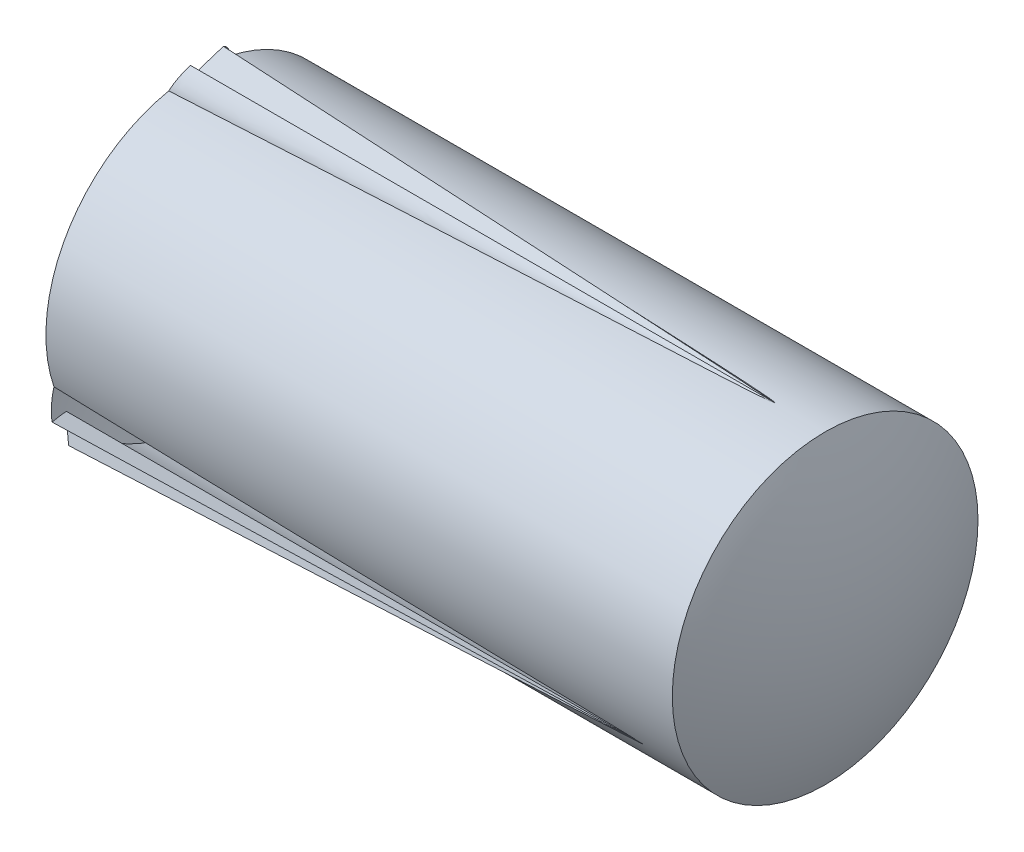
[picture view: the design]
ISO-10303-21;
HEADER;
FILE_DESCRIPTION(('STEP AP214'),'2;1');
FILE_NAME('part.step','',(''),(''),'','','');
FILE_SCHEMA(('AUTOMOTIVE_DESIGN { 1 0 10303 214 1 1 1 1 }'));
ENDSEC;
DATA;
#1=APPLICATION_CONTEXT('core data for automotive mechanical design processes');
#2=APPLICATION_PROTOCOL_DEFINITION('international standard','automotive_design',2000,#1);
#3=PRODUCT_CONTEXT('',#1,'mechanical');
#4=PRODUCT('Part','Part','',(#3));
#5=PRODUCT_RELATED_PRODUCT_CATEGORY('part','',(#4));
#6=PRODUCT_DEFINITION_FORMATION('','',#4);
#7=PRODUCT_DEFINITION_CONTEXT('part definition',#1,'design');
#8=PRODUCT_DEFINITION('design','',#6,#7);
#9=PRODUCT_DEFINITION_SHAPE('','',#8);
#10=(LENGTH_UNIT() NAMED_UNIT(*) SI_UNIT(.MILLI.,.METRE.));
#11=(NAMED_UNIT(*) PLANE_ANGLE_UNIT() SI_UNIT($,.RADIAN.));
#12=(NAMED_UNIT(*) SI_UNIT($,.STERADIAN.) SOLID_ANGLE_UNIT());
#13=UNCERTAINTY_MEASURE_WITH_UNIT(LENGTH_MEASURE(1.E-05),#10,'distance_accuracy_value','');
#14=(GEOMETRIC_REPRESENTATION_CONTEXT(3) GLOBAL_UNCERTAINTY_ASSIGNED_CONTEXT((#13)) GLOBAL_UNIT_ASSIGNED_CONTEXT((#10,
#11,#12)) REPRESENTATION_CONTEXT('',''));
#15=CARTESIAN_POINT('',(0.,0.,0.));
#16=DIRECTION('',(0.,0.,1.));
#17=DIRECTION('',(1.,0.,0.));
#18=AXIS2_PLACEMENT_3D('',#15,#16,#17);
#19=CARTESIAN_POINT('',(-1.5875,-0.291549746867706,0.495451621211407));
#20=CARTESIAN_POINT('',(1.3335,-0.372808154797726,0.644533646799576));
#21=CARTESIAN_POINT('',(-1.5875,-0.268799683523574,0.507669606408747));
#22=CARTESIAN_POINT('',(1.3335,-0.370586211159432,0.645702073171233));
#23=CARTESIAN_POINT('',(-1.5875,-0.24170191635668,0.529257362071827));
#24=CARTESIAN_POINT('',(1.3335,-0.36783750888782,0.648565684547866));
#25=CARTESIAN_POINT('',(-1.5875,-0.206920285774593,0.60421552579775));
#26=CARTESIAN_POINT('',(1.3335,-0.3646195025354,0.655930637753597));
#27=CARTESIAN_POINT('',(-1.5875,-0.203921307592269,0.659759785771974));
#28=CARTESIAN_POINT('',(1.3335,-0.364150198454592,0.660431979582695));
#29=CARTESIAN_POINT('',(-1.5875,-0.252793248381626,0.750760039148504));
#30=CARTESIAN_POINT('',(1.3335,-0.36882390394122,0.66931975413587));
#31=CARTESIAN_POINT('',(-1.5875,-0.300754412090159,0.778936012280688));
#32=CARTESIAN_POINT('',(1.3335,-0.372798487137,0.671484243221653));
#33=CARTESIAN_POINT('',(-1.5875,-0.38245310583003,0.791338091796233));
#34=CARTESIAN_POINT('',(1.3335,-0.380690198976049,0.673007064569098));
#35=CARTESIAN_POINT('',(-1.5875,-0.415415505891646,0.780670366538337));
#36=CARTESIAN_POINT('',(1.3335,-0.384607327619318,0.672365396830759));
#37=CARTESIAN_POINT('',(-1.5875,-0.460915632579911,0.756234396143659));
#38=CARTESIAN_POINT('',(1.3335,-0.389051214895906,0.670028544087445));
#39=CARTESIAN_POINT('',(-1.5875,-0.488013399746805,0.734646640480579));
#40=CARTESIAN_POINT('',(1.3335,-0.391799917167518,0.667164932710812));
#41=CARTESIAN_POINT('',(-1.5875,-0.522795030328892,0.659688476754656));
#42=CARTESIAN_POINT('',(1.3335,-0.395017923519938,0.659799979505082));
#43=CARTESIAN_POINT('',(-1.5875,-0.525794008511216,0.604144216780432));
#44=CARTESIAN_POINT('',(1.3335,-0.395487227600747,0.655298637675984));
#45=CARTESIAN_POINT('',(-1.5875,-0.476922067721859,0.513143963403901));
#46=CARTESIAN_POINT('',(1.3335,-0.390813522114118,0.646410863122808));
#47=CARTESIAN_POINT('',(-1.5875,-0.428960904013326,0.484967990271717));
#48=CARTESIAN_POINT('',(1.3335,-0.386838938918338,0.644246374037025));
#49=CARTESIAN_POINT('',(-1.5875,-0.347262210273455,0.472565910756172));
#50=CARTESIAN_POINT('',(1.3335,-0.378947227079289,0.64272355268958));
#51=CARTESIAN_POINT('',(-1.5875,-0.314299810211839,0.483233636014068));
#52=CARTESIAN_POINT('',(1.3335,-0.37503009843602,0.643365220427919));
#53=CARTESIAN_POINT('',(-1.5875,-0.291549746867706,0.495451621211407));
#54=CARTESIAN_POINT('',(1.3335,-0.372808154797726,0.644533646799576));
#55=B_SPLINE_SURFACE_WITH_KNOTS('',3,1,((#19,#20),(#21,#22),(#23,#24),(#25,#26),(#27,#28),(#29,
#30),(#31,#32),(#33,#34),(#35,#36),(#37,#38),(#39,#40),(#41,#42),(#43,#44),(#45,#46),(#47,#48),
(#49,#50),(#51,#52),(#53,#54)),.UNSPECIFIED.,.T.,.F.,.F.,(4,2,2,2,2,2,2,2,4),(2,2),(0.,0.125,
0.25,0.375,0.5,0.625,0.75,0.875,1.),(0.,1.),.UNSPECIFIED.);
#56=CARTESIAN_POINT('',(1.3332323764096,-0.387350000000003,0.670909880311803));
#57=CARTESIAN_POINT('',(1.32702789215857,-0.387657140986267,0.670992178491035));
#58=CARTESIAN_POINT('',(1.32082308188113,-0.387957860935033,0.671072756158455));
#59=CARTESIAN_POINT('',(1.28979763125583,-0.389434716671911,0.671468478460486));
#60=CARTESIAN_POINT('',(1.26497293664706,-0.390530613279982,0.671762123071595));
#61=CARTESIAN_POINT('',(1.14084574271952,-0.395925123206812,0.673207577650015));
#62=CARTESIAN_POINT('',(1.04153188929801,-0.399968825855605,0.674291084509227));
#63=CARTESIAN_POINT('',(0.743585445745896,-0.411975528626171,0.677508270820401));
#64=CARTESIAN_POINT('',(0.544947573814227,-0.419814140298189,0.679608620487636));
#65=CARTESIAN_POINT('',(0.0240320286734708,-0.440289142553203,0.685094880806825));
#66=CARTESIAN_POINT('',(-0.298247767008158,-0.452875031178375,0.688467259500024));
#67=CARTESIAN_POINT('',(-0.942809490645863,-0.477996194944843,0.695198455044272));
#68=CARTESIAN_POINT('',(-1.26509141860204,-0.490531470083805,0.698557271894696));
#69=CARTESIAN_POINT('',(-1.58737204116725,-0.50309757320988,0.701924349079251));
#70=B_SPLINE_CURVE_WITH_KNOTS('',3,(#56,#57,#58,#59,#60,#61,#62,#63,#64,#65,#66,#67,#68,#69),
.UNSPECIFIED.,.F.,.F.,(4,2,2,2,2,2,4),(0.,0.0186378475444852,0.0931893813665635,
0.391395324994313,0.987806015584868,1.95543526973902,2.9230645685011),.UNSPECIFIED.);
#71=CARTESIAN_POINT('',(1.33323237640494,-0.387350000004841,0.67090988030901));
#72=VERTEX_POINT('',#71);
#73=CARTESIAN_POINT('',(-1.54566934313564,-0.50147437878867,0.701489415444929));
#74=VERTEX_POINT('',#73);
#75=EDGE_CURVE('E84',#72,#74,#70,.T.);
#76=CARTESIAN_POINT('',(-1.54500744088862,-0.500125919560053,0.704044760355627));
#77=CARTESIAN_POINT('',(-1.54679609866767,-0.503995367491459,0.696996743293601));
#78=CARTESIAN_POINT('',(-1.54884127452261,-0.507167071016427,0.689682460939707));
#79=CARTESIAN_POINT('',(-1.55330634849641,-0.512259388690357,0.674759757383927));
#80=CARTESIAN_POINT('',(-1.55572508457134,-0.514183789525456,0.667152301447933));
#81=CARTESIAN_POINT('',(-1.56094778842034,-0.517021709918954,0.651425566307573));
#82=CARTESIAN_POINT('',(-1.56376545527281,-0.51787552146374,0.643300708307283));
#83=CARTESIAN_POINT('',(-1.56960974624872,-0.518430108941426,0.627076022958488));
#84=CARTESIAN_POINT('',(-1.57263654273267,-0.518129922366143,0.618976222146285));
#85=CARTESIAN_POINT('',(-1.57765132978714,-0.516704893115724,0.606038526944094));
#86=CARTESIAN_POINT('',(-1.57959276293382,-0.51594027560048,0.601140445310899));
#87=CARTESIAN_POINT('',(-1.58351689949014,-0.513963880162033,0.591468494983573));
#88=CARTESIAN_POINT('',(-1.58549947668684,-0.512753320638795,0.58669432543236));
#89=CARTESIAN_POINT('',(-1.5875,-0.511315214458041,0.581993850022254));
#90=B_SPLINE_CURVE_WITH_KNOTS('',3,(#76,#77,#78,#79,#80,#81,#82,#83,#84,#85,#86,#87,#88,#89),
.UNSPECIFIED.,.F.,.F.,(4,2,2,2,2,2,4),(0.,0.0246089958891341,0.0491429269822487,
0.0749917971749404,0.100862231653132,0.116815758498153,0.132726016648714),.UNSPECIFIED.);
#91=CARTESIAN_POINT('',(-1.5875,-0.511417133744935,0.581904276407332));
#92=VERTEX_POINT('',#91);
#93=EDGE_CURVE('E163',#74,#92,#90,.T.);
#94=CARTESIAN_POINT('',(-1.5875,-0.511315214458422,0.581993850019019));
#95=CARTESIAN_POINT('',(-1.5510388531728,-0.509953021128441,0.583190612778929));
#96=CARTESIAN_POINT('',(-1.51457762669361,-0.508587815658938,0.584381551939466));
#97=CARTESIAN_POINT('',(-1.33227107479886,-0.501746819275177,0.590307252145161));
#98=CARTESIAN_POINT('',(-1.18642459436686,-0.496226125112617,0.594955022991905));
#99=CARTESIAN_POINT('',(-0.894729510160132,-0.485091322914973,0.604068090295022));
#100=CARTESIAN_POINT('',(-0.748880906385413,-0.479477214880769,0.608533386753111));
#101=CARTESIAN_POINT('',(-0.457182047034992,-0.468154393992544,0.617286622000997));
#102=CARTESIAN_POINT('',(-0.311331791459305,-0.462445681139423,0.62157456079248));
#103=CARTESIAN_POINT('',(-0.0925559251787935,-0.453803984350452,0.627881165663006));
#104=CARTESIAN_POINT('',(-0.0196305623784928,-0.4509103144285,0.629962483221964));
#105=CARTESIAN_POINT('',(0.0897573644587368,-0.446546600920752,0.633055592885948));
#106=CARTESIAN_POINT('',(0.126219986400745,-0.445088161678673,0.634081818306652));
#107=CARTESIAN_POINT('',(0.308533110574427,-0.43777766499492,0.639188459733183));
#108=CARTESIAN_POINT('',(0.454383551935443,-0.431870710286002,0.643195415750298));
#109=CARTESIAN_POINT('',(0.673186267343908,-0.422813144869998,0.649154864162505));
#110=CARTESIAN_POINT('',(0.746141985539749,-0.41976036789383,0.651133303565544));
#111=CARTESIAN_POINT('',(0.891980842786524,-0.413540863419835,0.655101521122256));
#112=CARTESIAN_POINT('',(0.964863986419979,-0.41037424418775,0.65709128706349));
#113=CARTESIAN_POINT('',(1.07413626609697,-0.405328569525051,0.660206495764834));
#114=CARTESIAN_POINT('',(1.11053428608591,-0.403598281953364,0.661266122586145));
#115=CARTESIAN_POINT('',(1.1834214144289,-0.399887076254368,0.663517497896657));
#116=CARTESIAN_POINT('',(1.21991047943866,-0.397905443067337,0.664709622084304));
#117=CARTESIAN_POINT('',(1.27307232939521,-0.39436826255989,0.666810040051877));
#118=CARTESIAN_POINT('',(1.2897735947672,-0.393163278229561,0.667522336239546));
#119=CARTESIAN_POINT('',(1.31222269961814,-0.390998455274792,0.668790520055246));
#120=CARTESIAN_POINT('',(1.31800869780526,-0.390391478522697,0.669145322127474));
#121=CARTESIAN_POINT('',(1.32577045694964,-0.389280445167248,0.669791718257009));
#122=CARTESIAN_POINT('',(1.32777879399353,-0.388965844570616,0.669974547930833));
#123=CARTESIAN_POINT('',(1.33049611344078,-0.388382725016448,0.670312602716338));
#124=CARTESIAN_POINT('',(1.33122779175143,-0.38820969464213,0.670412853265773));
#125=CARTESIAN_POINT('',(1.33219296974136,-0.387896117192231,0.670594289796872));
#126=CARTESIAN_POINT('',(1.33244633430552,-0.387805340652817,0.670646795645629));
#127=CARTESIAN_POINT('',(1.33278210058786,-0.387650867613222,0.670736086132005));
#128=CARTESIAN_POINT('',(1.33287397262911,-0.387604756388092,0.670762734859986));
#129=CARTESIAN_POINT('',(1.33303654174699,-0.387508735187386,0.670818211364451));
#130=CARTESIAN_POINT('',(1.33310843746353,-0.387460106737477,0.670846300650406));
#131=CARTESIAN_POINT('',(1.33324349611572,-0.387346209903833,0.670912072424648));
#132=CARTESIAN_POINT('',(1.33330652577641,-0.387280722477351,0.670949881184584));
#133=CARTESIAN_POINT('',(1.33335671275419,-0.387130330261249,0.671036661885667));
#134=CARTESIAN_POINT('',(1.33334808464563,-0.387046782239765,0.671084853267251));
#135=CARTESIAN_POINT('',(1.33324399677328,-0.386814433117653,0.671218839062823));
#136=CARTESIAN_POINT('',(1.33305205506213,-0.386717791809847,0.671274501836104));
#137=CARTESIAN_POINT('',(1.33262977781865,-0.386527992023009,0.671383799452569));
#138=CARTESIAN_POINT('',(1.33240356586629,-0.386443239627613,0.671432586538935));
#139=CARTESIAN_POINT('',(1.33193531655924,-0.386291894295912,0.671519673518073));
#140=CARTESIAN_POINT('',(1.33169349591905,-0.386225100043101,0.671558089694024));
#141=CARTESIAN_POINT('',(1.33089374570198,-0.38601912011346,0.671676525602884));
#142=CARTESIAN_POINT('',(1.33033361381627,-0.385898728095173,0.67174569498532));
#143=CARTESIAN_POINT('',(1.32921036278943,-0.385677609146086,0.671872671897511));
#144=CARTESIAN_POINT('',(1.32864729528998,-0.385576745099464,0.671930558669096));
#145=CARTESIAN_POINT('',(1.32717273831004,-0.385328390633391,0.672073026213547));
#146=CARTESIAN_POINT('',(1.32625954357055,-0.385190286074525,0.67215218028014));
#147=CARTESIAN_POINT('',(1.32142647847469,-0.384497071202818,0.67254927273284));
#148=CARTESIAN_POINT('',(1.31748371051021,-0.384062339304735,0.67279749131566));
#149=CARTESIAN_POINT('',(1.30924317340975,-0.383224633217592,0.67327496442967));
#150=CARTESIAN_POINT('',(1.30494478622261,-0.382827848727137,0.673500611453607));
#151=CARTESIAN_POINT('',(1.28387217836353,-0.380984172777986,0.67454737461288));
#152=CARTESIAN_POINT('',(1.26706339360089,-0.379828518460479,0.675197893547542));
#153=CARTESIAN_POINT('',(1.23399421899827,-0.377699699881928,0.676390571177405));
#154=CARTESIAN_POINT('',(1.21773411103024,-0.376721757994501,0.676935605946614));
#155=CARTESIAN_POINT('',(1.16859487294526,-0.373902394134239,0.678499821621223));
#156=CARTESIAN_POINT('',(1.13570433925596,-0.372199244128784,0.679434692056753));
#157=CARTESIAN_POINT('',(1.0699157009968,-0.368919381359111,0.681220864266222));
#158=CARTESIAN_POINT('',(1.03701759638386,-0.367342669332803,0.682072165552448));
#159=CARTESIAN_POINT('',(0.937508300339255,-0.362662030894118,0.684579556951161));
#160=CARTESIAN_POINT('',(0.870890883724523,-0.359648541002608,0.686166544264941));
#161=CARTESIAN_POINT('',(0.737944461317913,-0.353691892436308,0.689255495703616));
#162=CARTESIAN_POINT('',(0.671615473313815,-0.350748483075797,0.690757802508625));
#163=CARTESIAN_POINT('',(0.539188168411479,-0.344890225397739,0.693701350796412));
#164=CARTESIAN_POINT('',(0.47308985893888,-0.341975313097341,0.69514278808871));
#165=CARTESIAN_POINT('',(0.274631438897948,-0.333218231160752,0.699405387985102));
#166=CARTESIAN_POINT('',(0.14227017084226,-0.327370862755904,0.702161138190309));
#167=CARTESIAN_POINT('',(-0.122593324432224,-0.315602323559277,0.707528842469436));
#168=CARTESIAN_POINT('',(-0.255095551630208,-0.309681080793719,0.710140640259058));
#169=CARTESIAN_POINT('',(-0.520028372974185,-0.297758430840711,0.715221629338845));
#170=CARTESIAN_POINT('',(-0.65245896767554,-0.291757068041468,0.717690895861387));
#171=CARTESIAN_POINT('',(-0.916206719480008,-0.279714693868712,0.722468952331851));
#172=CARTESIAN_POINT('',(-1.04752388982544,-0.273674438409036,0.724778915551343));
#173=CARTESIAN_POINT('',(-1.31506113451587,-0.261275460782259,0.729342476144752));
#174=CARTESIAN_POINT('',(-1.45128113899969,-0.254913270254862,0.731590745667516));
#175=CARTESIAN_POINT('',(-1.5875,-0.248500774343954,0.733762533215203));
#176=B_SPLINE_CURVE_WITH_KNOTS('',3,(#94,#95,#96,#97,#98,#99,#100,#101,#102,#103,#104,#105,#106,
#107,#108,#109,#110,#111,#112,#113,#114,#115,#116,#117,#118,#119,#120,#121,#122,#123,#124,#125,
#126,#127,#128,#129,#130,#131,#132,#133,#134,#135,#136,#137,#138,#139,#140,#141,#142,#143,#144,
#145,#146,#147,#148,#149,#150,#151,#152,#153,#154,#155,#156,#157,#158,#159,#160,#161,#162,#163,
#164,#165,#166,#167,#168,#169,#170,#171,#172,#173,#174,#175),.UNSPECIFIED.,.F.,.F.,(4,2,2,2,2,2,
2,2,2,2,2,2,2,2,2,2,2,2,2,2,2,2,2,2,2,2,2,2,2,2,2,2,2,2,2,2,2,2,2,2,4),(0.,0.109518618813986,
0.547593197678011,0.985667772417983,1.42374234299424,1.64277958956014,1.75229820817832,
2.19037278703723,2.40951203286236,2.62844811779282,2.73781196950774,2.84749424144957,
2.89776892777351,2.91524734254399,2.92136717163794,2.92363754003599,2.92445864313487,
2.92477568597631,2.92505134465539,2.92533078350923,2.92559390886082,2.92619169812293,
2.92695534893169,2.92771004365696,2.92944599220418,2.93116927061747,2.93395039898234,
2.94586710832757,2.95883561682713,3.00940854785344,3.05830591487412,3.15714640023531,
3.25598746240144,3.45609991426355,3.65533383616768,3.85386853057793,4.25142551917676,
4.64940594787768,5.04717435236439,5.44160317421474,5.8507641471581),.UNSPECIFIED.);
#177=EDGE_CURVE('E242',#92,#72,#176,.T.);
#178=ORIENTED_EDGE('',*,*,#75,.T.);
#179=ORIENTED_EDGE('',*,*,#93,.T.);
#180=ORIENTED_EDGE('',*,*,#177,.T.);
#181=EDGE_LOOP('',(#178,#179,#180));
#182=FACE_BOUND('',#181,.T.);
#183=ADVANCED_FACE('F73',(#182),#55,.T.);
#184=CARTESIAN_POINT('',(-1.58749999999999,-0.248339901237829,0.733812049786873));
#185=VERTEX_POINT('',#184);
#186=EDGE_CURVE('E156',#72,#185,#176,.T.);
#187=CARTESIAN_POINT('',(-1.58749999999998,-0.248500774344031,0.733762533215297));
#188=CARTESIAN_POINT('',(-1.58403028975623,-0.254337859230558,0.739990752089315));
#189=CARTESIAN_POINT('',(-1.58060899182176,-0.260678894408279,0.745758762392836));
#190=CARTESIAN_POINT('',(-1.57388632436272,-0.274300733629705,0.756346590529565));
#191=CARTESIAN_POINT('',(-1.57058676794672,-0.281591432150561,0.761154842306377));
#192=CARTESIAN_POINT('',(-1.56373468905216,-0.29805306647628,0.770286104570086));
#193=CARTESIAN_POINT('',(-1.56021844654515,-0.307342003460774,0.774428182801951));
#194=CARTESIAN_POINT('',(-1.55531311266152,-0.321819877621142,0.779277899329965));
#195=CARTESIAN_POINT('',(-1.55374297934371,-0.326723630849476,0.780665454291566));
#196=CARTESIAN_POINT('',(-1.55077705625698,-0.336706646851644,0.782878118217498));
#197=CARTESIAN_POINT('',(-1.54938117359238,-0.341785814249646,0.783703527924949));
#198=CARTESIAN_POINT('',(-1.54699295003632,-0.351115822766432,0.78473995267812));
#199=CARTESIAN_POINT('',(-1.54597327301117,-0.355350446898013,0.785035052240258));
#200=CARTESIAN_POINT('',(-1.5450074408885,-0.359596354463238,0.785172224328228));
#201=B_SPLINE_CURVE_WITH_KNOTS('',3,(#187,#188,#189,#190,#191,#192,#193,#194,#195,#196,#197,
#198,#199,#200),.UNSPECIFIED.,.F.,.F.,(4,2,2,2,2,2,4),(0.,0.027599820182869,0.0555144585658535,
0.0876157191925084,0.103586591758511,0.119548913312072,0.132626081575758),.UNSPECIFIED.);
#202=CARTESIAN_POINT('',(-1.54565892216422,-0.356763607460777,0.785059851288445));
#203=VERTEX_POINT('',#202);
#204=EDGE_CURVE('E155',#185,#203,#201,.T.);
#205=CARTESIAN_POINT('',(-1.58669387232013,-0.356335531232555,0.78665745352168));
#206=CARTESIAN_POINT('',(-1.55021728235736,-0.356716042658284,0.785237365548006));
#207=CARTESIAN_POINT('',(-1.51374069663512,-0.357096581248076,0.78381717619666));
#208=CARTESIAN_POINT('',(-1.33135779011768,-0.358999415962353,0.776715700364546));
#209=CARTESIAN_POINT('',(-1.18545153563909,-0.360522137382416,0.771032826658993));
#210=CARTESIAN_POINT('',(-0.747733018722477,-0.365091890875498,0.753978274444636));
#211=CARTESIAN_POINT('',(-0.45592100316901,-0.368140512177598,0.742600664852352));
#212=CARTESIAN_POINT('',(-0.0182048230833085,-0.372725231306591,0.725490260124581));
#213=CARTESIAN_POINT('',(0.127700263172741,-0.374255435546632,0.719779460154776));
#214=CARTESIAN_POINT('',(0.419509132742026,-0.377324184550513,0.708326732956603));
#215=CARTESIAN_POINT('',(0.565412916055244,-0.378862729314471,0.702584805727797));
#216=CARTESIAN_POINT('',(0.763145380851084,-0.380965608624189,0.694736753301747));
#217=CARTESIAN_POINT('',(0.814975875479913,-0.381518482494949,0.692673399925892));
#218=CARTESIAN_POINT('',(0.918635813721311,-0.382630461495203,0.688523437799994));
#219=CARTESIAN_POINT('',(0.97046525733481,-0.383189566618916,0.686436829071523));
#220=CARTESIAN_POINT('',(1.07412285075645,-0.384318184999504,0.682224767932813));
#221=CARTESIAN_POINT('',(1.12595100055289,-0.384887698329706,0.680099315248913));
#222=CARTESIAN_POINT('',(1.20368942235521,-0.385765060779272,0.676824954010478));
#223=CARTESIAN_POINT('',(1.2296016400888,-0.38606136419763,0.675719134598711));
#224=CARTESIAN_POINT('',(1.26846768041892,-0.386519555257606,0.674009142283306));
#225=CARTESIAN_POINT('',(1.2814226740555,-0.386674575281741,0.673430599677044));
#226=CARTESIAN_POINT('',(1.30733001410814,-0.386999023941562,0.672219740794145));
#227=CARTESIAN_POINT('',(1.32028236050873,-0.387168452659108,0.671587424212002));
#228=CARTESIAN_POINT('',(1.3332323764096,-0.387350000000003,0.670909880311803));
#229=B_SPLINE_CURVE_WITH_KNOTS('',3,(#205,#206,#207,#208,#209,#210,#211,#212,#213,#214,#215,
#216,#217,#218,#219,#220,#221,#222,#223,#224,#225,#226,#227,#228),.UNSPECIFIED.,.F.,.F.,(4,2,2,
2,2,2,2,2,2,2,2,4),(0.,0.109518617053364,0.547593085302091,1.42374202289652,1.86181649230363,
2.29989096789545,2.45551444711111,2.61113778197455,2.7667622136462,2.84457469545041,
2.88348110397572,2.92238773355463),.UNSPECIFIED.);
#230=EDGE_CURVE('E95',#203,#72,#229,.T.);
#231=ORIENTED_EDGE('',*,*,#186,.T.);
#232=ORIENTED_EDGE('',*,*,#204,.T.);
#233=ORIENTED_EDGE('',*,*,#230,.T.);
#234=EDGE_LOOP('',(#231,#232,#233));
#235=FACE_BOUND('',#234,.T.);
#236=ADVANCED_FACE('F159',(#235),#55,.T.);
#237=CARTESIAN_POINT('',(-1.5875,-0.283298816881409,-0.500215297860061));
#238=CARTESIAN_POINT('',(1.3335,-0.371778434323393,-0.645128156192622));
#239=CARTESIAN_POINT('',(-1.5875,-0.305254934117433,-0.486622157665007));
#240=CARTESIAN_POINT('',(1.3335,-0.373901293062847,-0.643788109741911));
#241=CARTESIAN_POINT('',(-1.5875,-0.337499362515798,-0.473948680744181));
#242=CARTESIAN_POINT('',(1.3335,-0.377755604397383,-0.642839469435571));
#243=CARTESIAN_POINT('',(-1.5875,-0.419805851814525,-0.481305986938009));
#244=CARTESIAN_POINT('',(1.3335,-0.38574284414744,-0.643735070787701));
#245=CARTESIAN_POINT('',(-1.5875,-0.469408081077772,-0.506480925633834));
#246=CARTESIAN_POINT('',(1.3335,-0.38987577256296,-0.64557931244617));
#247=CARTESIAN_POINT('',(-1.5875,-0.523780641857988,-0.594305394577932));
#248=CARTESIAN_POINT('',(1.3335,-0.395235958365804,-0.654070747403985));
#249=CARTESIAN_POINT('',(-1.5875,-0.524201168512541,-0.649928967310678));
#250=CARTESIAN_POINT('',(1.3335,-0.395123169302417,-0.658595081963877));
#251=CARTESIAN_POINT('',(-1.5875,-0.494092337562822,-0.726883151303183));
#252=CARTESIAN_POINT('',(1.3335,-0.392496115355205,-0.666190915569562));
#253=CARTESIAN_POINT('',(-1.5875,-0.468372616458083,-0.7500955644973));
#254=CARTESIAN_POINT('',(1.3335,-0.38998185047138,-0.669262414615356));
#255=CARTESIAN_POINT('',(-1.5875,-0.424460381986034,-0.777281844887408));
#256=CARTESIAN_POINT('',(1.3335,-0.385736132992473,-0.671942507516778));
#257=CARTESIAN_POINT('',(-1.5875,-0.392215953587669,-0.789955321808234));
#258=CARTESIAN_POINT('',(1.3335,-0.381881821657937,-0.672891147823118));
#259=CARTESIAN_POINT('',(-1.5875,-0.309909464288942,-0.782598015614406));
#260=CARTESIAN_POINT('',(1.3335,-0.37389458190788,-0.671995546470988));
#261=CARTESIAN_POINT('',(-1.5875,-0.260307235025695,-0.757423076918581));
#262=CARTESIAN_POINT('',(1.3335,-0.36976165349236,-0.670151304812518));
#263=CARTESIAN_POINT('',(-1.5875,-0.205934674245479,-0.669598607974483));
#264=CARTESIAN_POINT('',(1.3335,-0.364401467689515,-0.661659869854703));
#265=CARTESIAN_POINT('',(-1.5875,-0.205514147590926,-0.613975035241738));
#266=CARTESIAN_POINT('',(1.3335,-0.364514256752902,-0.657135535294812));
#267=CARTESIAN_POINT('',(-1.5875,-0.235622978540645,-0.537020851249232));
#268=CARTESIAN_POINT('',(1.3335,-0.367141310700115,-0.649539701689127));
#269=CARTESIAN_POINT('',(-1.5875,-0.261342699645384,-0.513808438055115));
#270=CARTESIAN_POINT('',(1.3335,-0.36965557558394,-0.646468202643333));
#271=CARTESIAN_POINT('',(-1.5875,-0.283298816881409,-0.500215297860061));
#272=CARTESIAN_POINT('',(1.3335,-0.371778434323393,-0.645128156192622));
#273=B_SPLINE_SURFACE_WITH_KNOTS('',3,1,((#237,#238),(#239,#240),(#241,#242),(#243,#244),(#245,
#246),(#247,#248),(#249,#250),(#251,#252),(#253,#254),(#255,#256),(#257,#258),(#259,#260),(#261,
#262),(#263,#264),(#265,#266),(#267,#268),(#269,#270),(#271,#272)),.UNSPECIFIED.,.T.,.F.,.F.,(4,
2,2,2,2,2,2,2,4),(2,2),(0.,0.125,0.25,0.375,0.5,0.625,0.75,0.875,1.),(0.,1.),.UNSPECIFIED.);
#274=CARTESIAN_POINT('',(1.3332323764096,-0.387349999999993,-0.670909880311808));
#275=CARTESIAN_POINT('',(1.32702789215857,-0.387267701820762,-0.671217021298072));
#276=CARTESIAN_POINT('',(1.32082308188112,-0.387187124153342,-0.671517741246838));
#277=CARTESIAN_POINT('',(1.28979763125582,-0.386791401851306,-0.672994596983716));
#278=CARTESIAN_POINT('',(1.26497293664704,-0.386497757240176,-0.674090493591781));
#279=CARTESIAN_POINT('',(1.14084574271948,-0.385052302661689,-0.679485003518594));
#280=CARTESIAN_POINT('',(1.04153188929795,-0.383968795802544,-0.683528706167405));
#281=CARTESIAN_POINT('',(0.743585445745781,-0.380751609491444,-0.695535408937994));
#282=CARTESIAN_POINT('',(0.544947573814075,-0.378651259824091,-0.703374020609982));
#283=CARTESIAN_POINT('',(0.0240320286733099,-0.373164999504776,-0.723849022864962));
#284=CARTESIAN_POINT('',(-0.298247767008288,-0.369792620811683,-0.736434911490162));
#285=CARTESIAN_POINT('',(-0.942809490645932,-0.363061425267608,-0.761556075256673));
#286=CARTESIAN_POINT('',(-1.26509141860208,-0.359702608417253,-0.774091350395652));
#287=CARTESIAN_POINT('',(-1.58737204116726,-0.356335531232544,-0.786657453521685));
#288=B_SPLINE_CURVE_WITH_KNOTS('',3,(#274,#275,#276,#277,#278,#279,#280,#281,#282,#283,#284,
#285,#286,#287),.UNSPECIFIED.,.F.,.F.,(4,2,2,2,2,2,4),(0.,0.0186378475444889,0.093189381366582,
0.391395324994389,0.987806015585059,1.95543526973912,2.92306456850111),.UNSPECIFIED.);
#289=CARTESIAN_POINT('',(1.33323237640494,-0.387349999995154,-0.670909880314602));
#290=VERTEX_POINT('',#289);
#291=CARTESIAN_POINT('',(-1.54566934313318,-0.356770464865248,-0.785034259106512));
#292=VERTEX_POINT('',#291);
#293=EDGE_CURVE('E168',#290,#292,#288,.T.);
#294=CARTESIAN_POINT('',(-1.54500744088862,-0.359657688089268,-0.785144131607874));
#295=CARTESIAN_POINT('',(-1.54679609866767,-0.351619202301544,-0.784971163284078));
#296=CARTESIAN_POINT('',(-1.54884127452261,-0.343698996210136,-0.784060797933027));
#297=CARTESIAN_POINT('',(-1.55330634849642,-0.328229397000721,-0.7810095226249));
#298=CARTESIAN_POINT('',(-1.55572508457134,-0.32067894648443,-0.778872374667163));
#299=CARTESIAN_POINT('',(-1.56094778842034,-0.305640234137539,-0.77346671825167));
#300=CARTESIAN_POINT('',(-1.56376545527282,-0.298176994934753,-0.770143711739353));
#301=CARTESIAN_POINT('',(-1.56960974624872,-0.283848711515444,-0.762511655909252));
#302=CARTESIAN_POINT('',(-1.57263654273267,-0.276984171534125,-0.75820178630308));
#303=CARTESIAN_POINT('',(-1.57765132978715,-0.266492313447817,-0.750498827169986));
#304=CARTESIAN_POINT('',(-1.57959276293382,-0.262632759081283,-0.747387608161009));
#305=CARTESIAN_POINT('',(-1.58351689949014,-0.255244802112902,-0.740840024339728));
#306=CARTESIAN_POINT('',(-1.58549947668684,-0.251715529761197,-0.737404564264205));
#307=CARTESIAN_POINT('',(-1.5875,-0.248363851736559,-0.73380889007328));
#308=B_SPLINE_CURVE_WITH_KNOTS('',3,(#294,#295,#296,#297,#298,#299,#300,#301,#302,#303,#304,
#305,#306,#307),.UNSPECIFIED.,.F.,.F.,(4,2,2,2,2,2,4),(0.,0.0246089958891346,0.0491429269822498,
0.0749917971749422,0.100862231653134,0.116815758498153,0.132726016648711),.UNSPECIFIED.);
#309=CARTESIAN_POINT('',(-1.5875,-0.248235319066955,-0.733852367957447));
#310=VERTEX_POINT('',#309);
#311=EDGE_CURVE('E327',#292,#310,#308,.T.);
#312=CARTESIAN_POINT('',(-1.5875,-0.248363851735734,-0.733808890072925));
#313=CARTESIAN_POINT('',(-1.55103885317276,-0.250081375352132,-0.733227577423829));
#314=CARTESIAN_POINT('',(-1.51457762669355,-0.251795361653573,-0.732640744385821));
#315=CARTESIAN_POINT('',(-1.33227107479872,-0.260347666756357,-0.729679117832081));
#316=CARTESIAN_POINT('',(-1.18642459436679,-0.267133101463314,-0.72722194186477));
#317=CARTESIAN_POINT('',(-0.894729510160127,-0.280592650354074,-0.722135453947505));
#318=CARTESIAN_POINT('',(-0.748880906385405,-0.287266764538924,-0.719506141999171));
#319=CARTESIAN_POINT('',(-0.457182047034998,-0.300508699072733,-0.714076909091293));
#320=CARTESIAN_POINT('',(-0.311331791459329,-0.307076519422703,-0.711276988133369));
#321=CARTESIAN_POINT('',(-0.0925559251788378,-0.316859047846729,-0.706946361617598));
#322=CARTESIAN_POINT('',(-0.0196305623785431,-0.320108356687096,-0.705481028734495));
#323=CARTESIAN_POINT('',(0.0897573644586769,-0.324968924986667,-0.703248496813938));
#324=CARTESIAN_POINT('',(0.126219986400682,-0.326586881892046,-0.702498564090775));
#325=CARTESIAN_POINT('',(0.308533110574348,-0.334664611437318,-0.69872080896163));
#326=CARTESIAN_POINT('',(0.454383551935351,-0.341088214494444,-0.69560871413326));
#327=CARTESIAN_POINT('',(0.673186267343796,-0.350778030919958,-0.690744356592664));
#328=CARTESIAN_POINT('',(0.74614198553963,-0.354017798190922,-0.689089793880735));
#329=CARTESIAN_POINT('',(0.891980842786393,-0.360564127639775,-0.685687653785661));
#330=CARTESIAN_POINT('',(0.964863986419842,-0.363870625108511,-0.68394016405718));
#331=CARTESIAN_POINT('',(1.07413626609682,-0.369091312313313,-0.681128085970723));
#332=CARTESIAN_POINT('',(1.11053428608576,-0.370874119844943,-0.680159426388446));
#333=CARTESIAN_POINT('',(1.18342141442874,-0.374679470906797,-0.678071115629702));
#334=CARTESIAN_POINT('',(1.2199104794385,-0.376702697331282,-0.676951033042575));
#335=CARTESIAN_POINT('',(1.27307232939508,-0.380290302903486,-0.674937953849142));
#336=CARTESIAN_POINT('',(1.28977359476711,-0.381509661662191,-0.674250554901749));
#337=CARTESIAN_POINT('',(1.31222269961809,-0.383690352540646,-0.673009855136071));
#338=CARTESIAN_POINT('',(1.31800869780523,-0.38430110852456,-0.672661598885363));
#339=CARTESIAN_POINT('',(1.32577045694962,-0.385416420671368,-0.67202261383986));
#340=CARTESIAN_POINT('',(1.32777879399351,-0.385732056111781,-0.671841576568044));
#341=CARTESIAN_POINT('',(1.33049611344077,-0.386316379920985,-0.671505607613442));
#342=CARTESIAN_POINT('',(1.33122779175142,-0.386489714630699,-0.671405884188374));
#343=CARTESIAN_POINT('',(1.33219296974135,-0.386803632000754,-0.671225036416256));
#344=CARTESIAN_POINT('',(1.33244633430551,-0.386894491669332,-0.671172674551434));
#345=CARTESIAN_POINT('',(1.33278210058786,-0.387049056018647,-0.671083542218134));
#346=CARTESIAN_POINT('',(1.3328739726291,-0.387095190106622,-0.671056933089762));
#347=CARTESIAN_POINT('',(1.33303654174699,-0.387191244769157,-0.671001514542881));
#348=CARTESIAN_POINT('',(1.33310843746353,-0.387239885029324,-0.670973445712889));
#349=CARTESIAN_POINT('',(1.33324349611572,-0.387353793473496,-0.670907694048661));
#350=CARTESIAN_POINT('',(1.33330652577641,-0.387419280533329,-0.670869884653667));
#351=CARTESIAN_POINT('',(1.33335671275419,-0.387569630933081,-0.67078303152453));
#352=CARTESIAN_POINT('',(1.33334808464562,-0.387653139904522,-0.670734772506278));
#353=CARTESIAN_POINT('',(1.33324399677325,-0.387885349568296,-0.670600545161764));
#354=CARTESIAN_POINT('',(1.33305205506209,-0.387981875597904,-0.670544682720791));
#355=CARTESIAN_POINT('',(1.33262977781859,-0.388171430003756,-0.670434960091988));
#356=CARTESIAN_POINT('',(1.33240356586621,-0.388256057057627,-0.670385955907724));
#357=CARTESIAN_POINT('',(1.33193531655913,-0.388407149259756,-0.670298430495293));
#358=CARTESIAN_POINT('',(1.33169349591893,-0.388473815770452,-0.670259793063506));
#359=CARTESIAN_POINT('',(1.3308937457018,-0.388679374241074,-0.670140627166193));
#360=CARTESIAN_POINT('',(1.33033361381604,-0.388799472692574,-0.67007094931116));
#361=CARTESIAN_POINT('',(1.32921036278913,-0.38901999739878,-0.669942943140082));
#362=CARTESIAN_POINT('',(1.32864729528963,-0.389120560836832,-0.669884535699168));
#363=CARTESIAN_POINT('',(1.32717273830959,-0.389368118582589,-0.669740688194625));
#364=CARTESIAN_POINT('',(1.32625954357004,-0.389505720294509,-0.669660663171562));
#365=CARTESIAN_POINT('',(1.32142647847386,-0.390196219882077,-0.669258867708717));
#366=CARTESIAN_POINT('',(1.31748371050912,-0.390628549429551,-0.66900648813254));
#367=CARTESIAN_POINT('',(1.30924317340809,-0.391460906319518,-0.668519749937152));
#368=CARTESIAN_POINT('',(1.30494478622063,-0.391854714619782,-0.668288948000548));
#369=CARTESIAN_POINT('',(1.28387217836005,-0.393683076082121,-0.667215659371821));
#370=CARTESIAN_POINT('',(1.26706339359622,-0.394824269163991,-0.666540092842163));
#371=CARTESIAN_POINT('',(1.23399421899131,-0.396921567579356,-0.66529282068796));
#372=CARTESIAN_POINT('',(1.21773411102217,-0.397882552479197,-0.664718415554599));
#373=CARTESIAN_POINT('',(1.16859487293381,-0.400646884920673,-0.663058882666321));
#374=CARTESIAN_POINT('',(1.13570433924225,-0.4023080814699,-0.662051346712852));
#375=CARTESIAN_POINT('',(1.06991570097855,-0.405494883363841,-0.660103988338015));
#376=CARTESIAN_POINT('',(1.03701759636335,-0.407020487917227,-0.659164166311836));
#377=CARTESIAN_POINT('',(0.937508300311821,-0.411532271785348,-0.656364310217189));
#378=CARTESIAN_POINT('',(0.870890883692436,-0.414413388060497,-0.654548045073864));
#379=CARTESIAN_POINT('',(0.737944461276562,-0.42006682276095,-0.650933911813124));
#380=CARTESIAN_POINT('',(0.671615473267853,-0.422839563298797,-0.649135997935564));
#381=CARTESIAN_POINT('',(0.53918816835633,-0.428317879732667,-0.645534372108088));
#382=CARTESIAN_POINT('',(0.473089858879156,-0.431023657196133,-0.643730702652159));
#383=CARTESIAN_POINT('',(0.274631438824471,-0.439093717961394,-0.638278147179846));
#384=CARTESIAN_POINT('',(0.142270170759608,-0.444403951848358,-0.634592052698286));
#385=CARTESIAN_POINT('',(-0.122593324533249,-0.454936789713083,-0.627084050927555));
#386=CARTESIAN_POINT('',(-0.255095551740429,-0.460159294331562,-0.623262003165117));
#387=CARTESIAN_POINT('',(-0.520028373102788,-0.470520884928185,-0.61547717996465));
#388=CARTESIAN_POINT('',(-0.652458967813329,-0.475660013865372,-0.611514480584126));
#389=CARTESIAN_POINT('',(-0.916206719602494,-0.485819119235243,-0.603474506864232));
#390=CARTESIAN_POINT('',(-1.04752388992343,-0.490839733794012,-0.599398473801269));
#391=CARTESIAN_POINT('',(-1.31506113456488,-0.500991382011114,-0.590942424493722));
#392=CARTESIAN_POINT('',(-1.4512811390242,-0.506119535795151,-0.586556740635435));
#393=CARTESIAN_POINT('',(-1.5875,-0.51120660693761,-0.582089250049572));
#394=B_SPLINE_CURVE_WITH_KNOTS('',3,(#312,#313,#314,#315,#316,#317,#318,#319,#320,#321,#322,
#323,#324,#325,#326,#327,#328,#329,#330,#331,#332,#333,#334,#335,#336,#337,#338,#339,#340,#341,
#342,#343,#344,#345,#346,#347,#348,#349,#350,#351,#352,#353,#354,#355,#356,#357,#358,#359,#360,
#361,#362,#363,#364,#365,#366,#367,#368,#369,#370,#371,#372,#373,#374,#375,#376,#377,#378,#379,
#380,#381,#382,#383,#384,#385,#386,#387,#388,#389,#390,#391,#392,#393),.UNSPECIFIED.,.F.,.F.,(4,
2,2,2,2,2,2,2,2,2,2,2,2,2,2,2,2,2,2,2,2,2,2,2,2,2,2,2,2,2,2,2,2,2,2,2,2,2,2,2,4),(0.,
0.109518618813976,0.547593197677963,0.985667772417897,1.42374234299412,1.64277958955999,
1.75229820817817,2.19037278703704,2.40951203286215,2.62844811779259,2.73781196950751,
2.84749424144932,2.89776892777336,2.91524734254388,2.92136717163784,2.92363754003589,
2.92445864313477,2.92477568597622,2.9250513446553,2.92533078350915,2.92559390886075,
2.92619169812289,2.9269553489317,2.92771004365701,2.92944599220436,2.93116927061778,
2.93395039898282,2.94586710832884,2.95883561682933,3.00940854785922,3.05830591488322,
3.15714640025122,3.25598746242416,3.45609991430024,3.65533383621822,3.85386853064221,
4.2514255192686,4.64940594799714,5.04717435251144,5.44160317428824,5.850764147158),.UNSPECIFIED.);
#395=EDGE_CURVE('E259',#310,#290,#394,.T.);
#396=ORIENTED_EDGE('',*,*,#293,.T.);
#397=ORIENTED_EDGE('',*,*,#311,.T.);
#398=ORIENTED_EDGE('',*,*,#395,.T.);
#399=EDGE_LOOP('',(#396,#397,#398));
#400=FACE_BOUND('',#399,.T.);
#401=ADVANCED_FACE('F274',(#400),#273,.T.);
#402=CARTESIAN_POINT('',(-1.5875,-0.511459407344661,-0.581867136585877));
#403=VERTEX_POINT('',#402);
#404=EDGE_CURVE('E263',#290,#403,#394,.T.);
#405=CARTESIAN_POINT('',(-1.58749999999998,-0.511206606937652,-0.582089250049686));
#406=CARTESIAN_POINT('',(-1.58403028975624,-0.513681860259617,-0.590258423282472));
#407=CARTESIAN_POINT('',(-1.58060899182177,-0.515506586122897,-0.598633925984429));
#408=CARTESIAN_POINT('',(-1.57388632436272,-0.517864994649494,-0.615724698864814));
#409=CARTESIAN_POINT('',(-1.57058676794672,-0.518383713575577,-0.624442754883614));
#410=CARTESIAN_POINT('',(-1.56373468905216,-0.518060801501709,-0.64326457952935));
#411=CARTESIAN_POINT('',(-1.56021844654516,-0.51700347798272,-0.653380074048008));
#412=CARTESIAN_POINT('',(-1.55531311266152,-0.513964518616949,-0.668343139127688));
#413=CARTESIAN_POINT('',(-1.55374297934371,-0.512714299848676,-0.673283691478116));
#414=CARTESIAN_POINT('',(-1.55077705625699,-0.509639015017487,-0.683035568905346));
#415=CARTESIAN_POINT('',(-1.54938117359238,-0.507814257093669,-0.687846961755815));
#416=CARTESIAN_POINT('',(-1.54699295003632,-0.504046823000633,-0.696445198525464));
#417=CARTESIAN_POINT('',(-1.54597327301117,-0.502185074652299,-0.700260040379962));
#418=CARTESIAN_POINT('',(-1.5450074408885,-0.500180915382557,-0.704005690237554));
#419=B_SPLINE_CURVE_WITH_KNOTS('',3,(#405,#406,#407,#408,#409,#410,#411,#412,#413,#414,#415,
#416,#417,#418),.UNSPECIFIED.,.F.,.F.,(4,2,2,2,2,2,4),(0.,0.0275998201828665,0.0555144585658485,
0.0876157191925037,0.103586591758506,0.119548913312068,0.132626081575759),.UNSPECIFIED.);
#420=CARTESIAN_POINT('',(-1.54565892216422,-0.501499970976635,-0.701496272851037));
#421=VERTEX_POINT('',#420);
#422=EDGE_CURVE('E316',#403,#421,#419,.T.);
#423=CARTESIAN_POINT('',(-1.58669387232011,-0.50309757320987,-0.701924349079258));
#424=CARTESIAN_POINT('',(-1.55021728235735,-0.501677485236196,-0.701543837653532));
#425=CARTESIAN_POINT('',(-1.51374069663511,-0.50025729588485,-0.70116329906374));
#426=CARTESIAN_POINT('',(-1.33135779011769,-0.493155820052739,-0.699260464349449));
#427=CARTESIAN_POINT('',(-1.1854515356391,-0.4874729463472,-0.697737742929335));
#428=CARTESIAN_POINT('',(-0.747733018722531,-0.47041839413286,-0.693167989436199));
#429=CARTESIAN_POINT('',(-0.45592100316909,-0.459040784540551,-0.690119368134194));
#430=CARTESIAN_POINT('',(-0.018204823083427,-0.441930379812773,-0.685534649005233));
#431=CARTESIAN_POINT('',(0.12770026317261,-0.436219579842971,-0.684004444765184));
#432=CARTESIAN_POINT('',(0.41950913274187,-0.424766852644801,-0.680935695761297));
#433=CARTESIAN_POINT('',(0.565412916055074,-0.419024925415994,-0.679397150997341));
#434=CARTESIAN_POINT('',(0.763145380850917,-0.411176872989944,-0.677294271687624));
#435=CARTESIAN_POINT('',(0.814975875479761,-0.409113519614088,-0.676741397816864));
#436=CARTESIAN_POINT('',(0.918635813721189,-0.404963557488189,-0.675629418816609));
#437=CARTESIAN_POINT('',(0.970465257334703,-0.402876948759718,-0.675070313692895));
#438=CARTESIAN_POINT('',(1.07412285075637,-0.398664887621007,-0.673941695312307));
#439=CARTESIAN_POINT('',(1.12595100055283,-0.396539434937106,-0.673372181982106));
#440=CARTESIAN_POINT('',(1.20368942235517,-0.39326507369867,-0.672494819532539));
#441=CARTESIAN_POINT('',(1.22960164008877,-0.392159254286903,-0.672198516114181));
#442=CARTESIAN_POINT('',(1.26846768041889,-0.390449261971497,-0.671740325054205));
#443=CARTESIAN_POINT('',(1.28142267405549,-0.389870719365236,-0.67158530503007));
#444=CARTESIAN_POINT('',(1.30733001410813,-0.388659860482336,-0.671260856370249));
#445=CARTESIAN_POINT('',(1.32028236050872,-0.388027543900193,-0.671091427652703));
#446=CARTESIAN_POINT('',(1.3332323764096,-0.387349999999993,-0.670909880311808));
#447=B_SPLINE_CURVE_WITH_KNOTS('',3,(#423,#424,#425,#426,#427,#428,#429,#430,#431,#432,#433,
#434,#435,#436,#437,#438,#439,#440,#441,#442,#443,#444,#445,#446),.UNSPECIFIED.,.F.,.F.,(4,2,2,
2,2,2,2,2,2,2,2,4),(0.,0.109518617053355,0.547593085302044,1.4237420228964,1.86181649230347,
2.29989096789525,2.45551444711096,2.61113778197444,2.76676221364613,2.84457469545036,
2.88348110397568,2.92238773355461),.UNSPECIFIED.);
#448=EDGE_CURVE('E103',#421,#290,#447,.T.);
#449=ORIENTED_EDGE('',*,*,#404,.T.);
#450=ORIENTED_EDGE('',*,*,#422,.T.);
#451=ORIENTED_EDGE('',*,*,#448,.T.);
#452=EDGE_LOOP('',(#449,#450,#451));
#453=FACE_BOUND('',#452,.T.);
#454=ADVANCED_FACE('F278',(#453),#273,.T.);
#455=CARTESIAN_POINT('',(-1.5875,0.574848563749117,0.00476367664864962));
#456=CARTESIAN_POINT('',(1.3335,0.744586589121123,0.000594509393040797));
#457=CARTESIAN_POINT('',(-1.5875,0.574054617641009,-0.021047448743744));
#458=CARTESIAN_POINT('',(1.3335,0.744487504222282,-0.00191396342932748));
#459=CARTESIAN_POINT('',(-1.5875,0.57920127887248,-0.0553086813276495));
#460=CARTESIAN_POINT('',(1.3335,0.745593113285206,-0.00572621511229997));
#461=CARTESIAN_POINT('',(-1.5875,0.626726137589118,-0.122909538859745));
#462=CARTESIAN_POINT('',(1.3335,0.750362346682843,-0.0121955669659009));
#463=CARTESIAN_POINT('',(-1.5875,0.673329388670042,-0.153278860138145));
#464=CARTESIAN_POINT('',(1.3335,0.754025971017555,-0.0148526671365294));
#465=CARTESIAN_POINT('',(-1.5875,0.776573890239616,-0.156454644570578));
#466=CARTESIAN_POINT('',(1.3335,0.764059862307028,-0.01524900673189));
#467=CARTESIAN_POINT('',(-1.5875,0.824955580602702,-0.129007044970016));
#468=CARTESIAN_POINT('',(1.3335,0.767921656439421,-0.0128891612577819));
#469=CARTESIAN_POINT('',(-1.5875,0.876545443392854,-0.0644549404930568));
#470=CARTESIAN_POINT('',(1.3335,0.773186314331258,-0.00681614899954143));
#471=CARTESIAN_POINT('',(-1.5875,0.883788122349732,-0.0305748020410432));
#472=CARTESIAN_POINT('',(1.3335,0.774589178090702,-0.00310298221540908));
#473=CARTESIAN_POINT('',(-1.5875,0.885376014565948,0.021047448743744));
#474=CARTESIAN_POINT('',(1.3335,0.774787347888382,0.00191396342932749));
#475=CARTESIAN_POINT('',(-1.5875,0.880229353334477,0.0553086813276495));
#476=CARTESIAN_POINT('',(1.3335,0.773681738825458,0.00572621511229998));
#477=CARTESIAN_POINT('',(-1.5875,0.832704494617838,0.122909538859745));
#478=CARTESIAN_POINT('',(1.3335,0.768912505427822,0.0121955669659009));
#479=CARTESIAN_POINT('',(-1.5875,0.786101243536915,0.153278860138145));
#480=CARTESIAN_POINT('',(1.3335,0.76524888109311,0.0148526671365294));
#481=CARTESIAN_POINT('',(-1.5875,0.68285674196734,0.156454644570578));
#482=CARTESIAN_POINT('',(1.3335,0.755214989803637,0.01524900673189));
#483=CARTESIAN_POINT('',(-1.5875,0.634475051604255,0.129007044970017));
#484=CARTESIAN_POINT('',(1.3335,0.751353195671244,0.0128891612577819));
#485=CARTESIAN_POINT('',(-1.5875,0.582885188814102,0.0644549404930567));
#486=CARTESIAN_POINT('',(1.3335,0.746088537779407,0.00681614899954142));
#487=CARTESIAN_POINT('',(-1.5875,0.575642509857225,0.0305748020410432));
#488=CARTESIAN_POINT('',(1.3335,0.744685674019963,0.00310298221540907));
#489=CARTESIAN_POINT('',(-1.5875,0.574848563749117,0.00476367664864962));
#490=CARTESIAN_POINT('',(1.3335,0.744586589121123,0.000594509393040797));
#491=B_SPLINE_SURFACE_WITH_KNOTS('',3,1,((#455,#456),(#457,#458),(#459,#460),(#461,#462),(#463,
#464),(#465,#466),(#467,#468),(#469,#470),(#471,#472),(#473,#474),(#475,#476),(#477,#478),(#479,
#480),(#481,#482),(#483,#484),(#485,#486),(#487,#488),(#489,#490)),.UNSPECIFIED.,.T.,.F.,.F.,(4,
2,2,2,2,2,2,2,4),(2,2),(0.,0.125,0.25,0.375,0.5,0.625,0.75,0.875,1.),(0.,1.),.UNSPECIFIED.);
#492=CARTESIAN_POINT('',(1.3332323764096,0.7747,0.));
#493=CARTESIAN_POINT('',(1.32702789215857,0.774924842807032,0.000224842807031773));
#494=CARTESIAN_POINT('',(1.32082308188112,0.775144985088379,0.000444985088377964));
#495=CARTESIAN_POINT('',(1.28979763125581,0.776226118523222,0.00152611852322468));
#496=CARTESIAN_POINT('',(1.26497293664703,0.777028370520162,0.00232837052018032));
#497=CARTESIAN_POINT('',(1.14084574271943,0.780977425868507,0.00627742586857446));
#498=CARTESIAN_POINT('',(1.04153188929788,0.783937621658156,0.00923762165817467));
#499=CARTESIAN_POINT('',(0.743585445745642,0.792727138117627,0.0180271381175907));
#500=CARTESIAN_POINT('',(0.544947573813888,0.798465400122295,0.0237654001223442));
#501=CARTESIAN_POINT('',(0.0240320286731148,0.813454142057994,0.0387541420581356));
#502=CARTESIAN_POINT('',(-0.298247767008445,0.822667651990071,0.0479676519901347));
#503=CARTESIAN_POINT('',(-0.942809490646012,0.84105762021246,0.0663576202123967));
#504=CARTESIAN_POINT('',(-1.26509141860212,0.850234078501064,0.0755340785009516));
#505=CARTESIAN_POINT('',(-1.58737204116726,0.859433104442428,0.0847331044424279));
#506=B_SPLINE_CURVE_WITH_KNOTS('',3,(#492,#493,#494,#495,#496,#497,#498,#499,#500,#501,#502,
#503,#504,#505),.UNSPECIFIED.,.F.,.F.,(4,2,2,2,2,2,4),(0.,0.0186378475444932,0.0931893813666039,
0.391395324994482,0.987806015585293,1.95543526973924,2.92306456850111),.UNSPECIFIED.);
#507=CARTESIAN_POINT('',(1.33323237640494,0.7747,5.5866146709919E-12));
#508=VERTEX_POINT('',#507);
#509=CARTESIAN_POINT('',(-1.54566934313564,0.85824484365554,0.0835448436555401));
#510=VERTEX_POINT('',#509);
#511=EDGE_CURVE('E387',#508,#510,#506,.T.);
#512=CARTESIAN_POINT('',(-1.54500744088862,0.859783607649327,0.0810993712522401));
#513=CARTESIAN_POINT('',(-1.54679609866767,0.855614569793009,0.0879744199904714));
#514=CARTESIAN_POINT('',(-1.54884127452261,0.85086606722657,0.0943783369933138));
#515=CARTESIAN_POINT('',(-1.55330634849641,0.840488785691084,0.106249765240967));
#516=CARTESIAN_POINT('',(-1.55572508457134,0.834862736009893,0.111720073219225));
#517=CARTESIAN_POINT('',(-1.56094778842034,0.822661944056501,0.122041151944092));
#518=CARTESIAN_POINT('',(-1.56376545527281,0.816052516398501,0.126843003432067));
#519=CARTESIAN_POINT('',(-1.56960974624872,0.802278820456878,0.135435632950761));
#520=CARTESIAN_POINT('',(-1.57263654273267,0.795114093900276,0.139225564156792));
#521=CARTESIAN_POINT('',(-1.57765132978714,0.783197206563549,0.144460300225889));
#522=CARTESIAN_POINT('',(-1.57959276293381,0.778573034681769,0.146247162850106));
#523=CARTESIAN_POINT('',(-1.58351689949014,0.76920868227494,0.149371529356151));
#524=CARTESIAN_POINT('',(-1.58549947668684,0.764468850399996,0.150710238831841));
#525=CARTESIAN_POINT('',(-1.5875,0.759679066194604,0.151815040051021));
#526=B_SPLINE_CURVE_WITH_KNOTS('',3,(#512,#513,#514,#515,#516,#517,#518,#519,#520,#521,#522,
#523,#524,#525),.UNSPECIFIED.,.F.,.F.,(4,2,2,2,2,2,4),(0.,0.0246089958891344,0.0491429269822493,
0.0749917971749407,0.100862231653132,0.116815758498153,0.132726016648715),.UNSPECIFIED.);
#527=CARTESIAN_POINT('',(-1.5875,0.759652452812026,0.151948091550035));
#528=VERTEX_POINT('',#527);
#529=EDGE_CURVE('E214',#510,#528,#526,.T.);
#530=CARTESIAN_POINT('',(-1.5875,0.759679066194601,0.151815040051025));
#531=CARTESIAN_POINT('',(-1.55103885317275,0.760034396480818,0.150036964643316));
#532=CARTESIAN_POINT('',(-1.51457762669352,0.760383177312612,0.148259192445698));
#533=CARTESIAN_POINT('',(-1.33227107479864,0.762094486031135,0.139371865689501));
#534=CARTESIAN_POINT('',(-1.18642459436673,0.763359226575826,0.132266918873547));
#535=CARTESIAN_POINT('',(-0.89472951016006,0.765683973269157,0.118067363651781));
#536=CARTESIAN_POINT('',(-0.748880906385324,0.766743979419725,0.11097275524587));
#537=CARTESIAN_POINT('',(-0.457182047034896,0.768663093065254,0.0967902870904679));
#538=CARTESIAN_POINT('',(-0.311331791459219,0.769522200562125,0.0897024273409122));
#539=CARTESIAN_POINT('',(-0.0925559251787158,0.77066303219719,0.0790651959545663));
#540=CARTESIAN_POINT('',(-0.0196305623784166,0.771018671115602,0.0755185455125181));
#541=CARTESIAN_POINT('',(0.08975736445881,0.771515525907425,0.0701929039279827));
#542=CARTESIAN_POINT('',(0.126219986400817,0.771675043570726,0.0684167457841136));
#543=CARTESIAN_POINT('',(0.308533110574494,0.772442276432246,0.0595323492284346));
#544=CARTESIAN_POINT('',(0.454383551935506,0.772958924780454,0.0524132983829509));
#545=CARTESIAN_POINT('',(0.673186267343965,0.773591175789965,0.0415894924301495));
#546=CARTESIAN_POINT('',(0.746141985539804,0.773778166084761,0.0379564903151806));
#547=CARTESIAN_POINT('',(0.891980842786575,0.77410499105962,0.0305861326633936));
#548=CARTESIAN_POINT('',(0.964863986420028,0.774244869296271,0.026848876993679));
#549=CARTESIAN_POINT('',(1.07413626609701,0.774419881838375,0.0209215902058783));
#550=CARTESIAN_POINT('',(1.11053428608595,0.774472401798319,0.0188933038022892));
#551=CARTESIAN_POINT('',(1.18342141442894,0.774566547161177,0.0145536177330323));
#552=CARTESIAN_POINT('',(1.2199104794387,0.774608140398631,0.0122414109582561));
#553=CARTESIAN_POINT('',(1.27307232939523,0.77465856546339,0.00812791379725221));
#554=CARTESIAN_POINT('',(1.28977359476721,0.774672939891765,0.00672821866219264));
#555=CARTESIAN_POINT('',(1.31222269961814,0.774688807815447,0.0042193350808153));
#556=CARTESIAN_POINT('',(1.31800869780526,0.774692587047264,0.00351627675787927));
#557=CARTESIAN_POINT('',(1.32577045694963,0.774696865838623,0.00223089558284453));
#558=CARTESIAN_POINT('',(1.32777879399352,0.774697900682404,0.00186702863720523));
#559=CARTESIAN_POINT('',(1.33049611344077,0.774699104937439,0.00119300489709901));
#560=CARTESIAN_POINT('',(1.33122779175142,0.774699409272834,0.000993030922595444));
#561=CARTESIAN_POINT('',(1.33219296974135,0.77469974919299,0.000630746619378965));
#562=CARTESIAN_POINT('',(1.33244633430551,0.774699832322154,0.000525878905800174));
#563=CARTESIAN_POINT('',(1.33278210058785,0.774699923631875,0.000347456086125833));
#564=CARTESIAN_POINT('',(1.3328739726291,0.77469994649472,0.000294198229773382));
#565=CARTESIAN_POINT('',(1.33303654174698,0.774699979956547,0.000183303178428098));
#566=CARTESIAN_POINT('',(1.33310843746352,0.774699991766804,0.000127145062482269));
#567=CARTESIAN_POINT('',(1.33324349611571,0.774700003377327,-4.37837598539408E-06));
#568=CARTESIAN_POINT('',(1.3333065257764,0.774700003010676,-7.99965309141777E-05));
#569=CARTESIAN_POINT('',(1.33335671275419,0.774699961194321,-0.000253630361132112));
#570=CARTESIAN_POINT('',(1.33334808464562,0.774699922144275,-0.000350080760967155));
#571=CARTESIAN_POINT('',(1.33324399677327,0.77469978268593,-0.000618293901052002));
#572=CARTESIAN_POINT('',(1.33305205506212,0.774699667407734,-0.000729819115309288));
#573=CARTESIAN_POINT('',(1.33262977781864,0.774699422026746,-0.000948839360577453));
#574=CARTESIAN_POINT('',(1.33240356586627,0.774699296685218,-0.00104663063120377));
#575=CARTESIAN_POINT('',(1.33193531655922,0.77469904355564,-0.00122124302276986));
#576=CARTESIAN_POINT('',(1.33169349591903,0.774698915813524,-0.00129829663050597));
#577=CARTESIAN_POINT('',(1.33089374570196,0.774698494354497,-0.00153589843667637));
#578=CARTESIAN_POINT('',(1.33033361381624,0.774698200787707,-0.00167474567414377));
#579=CARTESIAN_POINT('',(1.3292103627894,0.774697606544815,-0.00192972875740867));
#580=CARTESIAN_POINT('',(1.32864729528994,0.77469730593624,-0.00204602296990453));
#581=CARTESIAN_POINT('',(1.32717273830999,0.774696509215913,-0.00233233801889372));
#582=CARTESIAN_POINT('',(1.32625954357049,0.774696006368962,-0.00249151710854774));
#583=CARTESIAN_POINT('',(1.32142647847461,0.774693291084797,-0.00329040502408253));
#584=CARTESIAN_POINT('',(1.3174837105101,0.774690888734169,-0.00379100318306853));
#585=CARTESIAN_POINT('',(1.30924317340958,0.774685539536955,-0.00475521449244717));
#586=CARTESIAN_POINT('',(1.3049447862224,0.774682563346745,-0.00521166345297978));
#587=CARTESIAN_POINT('',(1.28387217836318,0.774667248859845,-0.00733171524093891));
#588=CARTESIAN_POINT('',(1.26706339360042,0.774652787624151,-0.00865780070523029));
#589=CARTESIAN_POINT('',(1.23399421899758,0.774621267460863,-0.0110977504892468));
#590=CARTESIAN_POINT('',(1.21773411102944,0.774604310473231,-0.0122171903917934));
#591=CARTESIAN_POINT('',(1.16859487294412,0.774549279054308,-0.0154409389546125));
#592=CARTESIAN_POINT('',(1.1357043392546,0.774507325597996,-0.0173833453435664));
#593=CARTESIAN_POINT('',(1.06991570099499,0.774414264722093,-0.0211168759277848));
#594=CARTESIAN_POINT('',(1.03701759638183,0.774363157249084,-0.0229079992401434));
#595=CARTESIAN_POINT('',(0.937508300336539,0.774194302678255,-0.0282152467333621));
#596=CARTESIAN_POINT('',(0.870890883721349,0.774061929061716,-0.0316184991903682));
#597=CARTESIAN_POINT('',(0.737944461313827,0.773758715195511,-0.03832158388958));
#598=CARTESIAN_POINT('',(0.671615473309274,0.77358804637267,-0.0416218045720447));
#599=CARTESIAN_POINT('',(0.539188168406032,0.773208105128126,-0.0481669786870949));
#600=CARTESIAN_POINT('',(0.473089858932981,0.772998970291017,-0.0514120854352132));
#601=CARTESIAN_POINT('',(0.274631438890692,0.772311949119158,-0.0611272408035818));
#602=CARTESIAN_POINT('',(0.142270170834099,0.771774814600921,-0.0675690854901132));
#603=CARTESIAN_POINT('',(-0.122593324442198,0.770539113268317,-0.0804447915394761));
#604=CARTESIAN_POINT('',(-0.255095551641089,0.76984037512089,-0.0868786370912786));
#605=CARTESIAN_POINT('',(-0.52002837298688,0.768279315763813,-0.0997444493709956));
#606=CARTESIAN_POINT('',(-0.652458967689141,0.767417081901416,-0.106176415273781));
#607=CARTESIAN_POINT('',(-0.91620671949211,0.765533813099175,-0.118994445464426));
#608=CARTESIAN_POINT('',(-1.04752388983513,0.764514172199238,-0.125380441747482));
#609=CARTESIAN_POINT('',(-1.31506113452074,0.762266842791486,-0.138400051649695));
#610=CARTESIAN_POINT('',(-1.45128113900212,0.761032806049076,-0.145034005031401));
#611=CARTESIAN_POINT('',(-1.5875,0.759707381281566,-0.151673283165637));
#612=B_SPLINE_CURVE_WITH_KNOTS('',3,(#530,#531,#532,#533,#534,#535,#536,#537,#538,#539,#540,
#541,#542,#543,#544,#545,#546,#547,#548,#549,#550,#551,#552,#553,#554,#555,#556,#557,#558,#559,
#560,#561,#562,#563,#564,#565,#566,#567,#568,#569,#570,#571,#572,#573,#574,#575,#576,#577,#578,
#579,#580,#581,#582,#583,#584,#585,#586,#587,#588,#589,#590,#591,#592,#593,#594,#595,#596,#597,
#598,#599,#600,#601,#602,#603,#604,#605,#606,#607,#608,#609,#610,#611),.UNSPECIFIED.,.F.,.F.,(4,
2,2,2,2,2,2,2,2,2,2,2,2,2,2,2,2,2,2,2,2,2,2,2,2,2,2,2,2,2,2,2,2,2,2,2,2,2,2,2,4),(0.,
0.109518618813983,0.547593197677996,0.985667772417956,1.42374234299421,1.64277958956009,
1.75229820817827,2.19037278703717,2.40951203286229,2.62844811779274,2.73781196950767,
2.84749424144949,2.89776892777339,2.91524734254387,2.92136717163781,2.92363754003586,
2.92445864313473,2.92477568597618,2.92505134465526,2.9253307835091,2.92559390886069,
2.92619169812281,2.92695534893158,2.92771004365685,2.92944599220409,2.93116927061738,
2.93395039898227,2.94586710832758,2.95883561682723,3.00940854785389,3.0583059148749,
3.15714640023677,3.25598746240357,3.45609991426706,3.65533383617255,3.85386853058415,
4.25142551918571,4.64940594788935,5.04717435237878,5.44160317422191,5.85076414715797),.UNSPECIFIED.);
#613=EDGE_CURVE('E248',#528,#508,#612,.T.);
#614=ORIENTED_EDGE('',*,*,#511,.T.);
#615=ORIENTED_EDGE('',*,*,#529,.T.);
#616=ORIENTED_EDGE('',*,*,#613,.T.);
#617=EDGE_LOOP('',(#614,#615,#616));
#618=FACE_BOUND('',#617,.T.);
#619=ADVANCED_FACE('F355',(#618),#491,.T.);
#620=CARTESIAN_POINT('',(-1.58749999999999,0.759669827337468,-0.151837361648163));
#621=VERTEX_POINT('',#620);
#622=EDGE_CURVE('E390',#508,#621,#612,.T.);
#623=CARTESIAN_POINT('',(-1.58749999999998,0.759707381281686,-0.151673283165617));
#624=CARTESIAN_POINT('',(-1.58403028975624,0.768019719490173,-0.149732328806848));
#625=CARTESIAN_POINT('',(-1.58060899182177,0.776185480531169,-0.147124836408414));
#626=CARTESIAN_POINT('',(-1.57388632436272,0.792165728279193,-0.140621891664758));
#627=CARTESIAN_POINT('',(-1.57058676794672,0.799975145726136,-0.136712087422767));
#628=CARTESIAN_POINT('',(-1.56373468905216,0.816113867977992,-0.127021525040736));
#629=CARTESIAN_POINT('',(-1.56021844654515,0.824345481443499,-0.121048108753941));
#630=CARTESIAN_POINT('',(-1.55531311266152,0.835784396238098,-0.110934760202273));
#631=CARTESIAN_POINT('',(-1.5537429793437,0.839437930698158,-0.107381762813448));
#632=CARTESIAN_POINT('',(-1.55077705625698,0.846345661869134,-0.0998425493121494));
#633=CARTESIAN_POINT('',(-1.54938117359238,0.849600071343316,-0.0958565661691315));
#634=CARTESIAN_POINT('',(-1.54699295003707,0.855162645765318,-0.0882947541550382));
#635=CARTESIAN_POINT('',(-1.54597327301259,0.857535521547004,-0.08477501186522));
#636=CARTESIAN_POINT('',(-1.54500744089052,0.859777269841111,-0.0811665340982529));
#637=B_SPLINE_CURVE_WITH_KNOTS('',3,(#623,#624,#625,#626,#627,#628,#629,#630,#631,#632,#633,
#634,#635,#636),.UNSPECIFIED.,.F.,.F.,(4,2,2,2,2,2,4),(0.,0.0275998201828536,0.0555144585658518,
0.087615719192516,0.103586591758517,0.119548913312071,0.132626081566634),.UNSPECIFIED.);
#638=CARTESIAN_POINT('',(-1.54565892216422,0.858263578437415,-0.0835635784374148));
#639=VERTEX_POINT('',#638);
#640=EDGE_CURVE('E340',#621,#639,#637,.T.);
#641=CARTESIAN_POINT('',(-1.58669387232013,0.859433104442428,-0.0847331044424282));
#642=CARTESIAN_POINT('',(-1.55021728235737,0.858393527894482,-0.0836935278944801));
#643=CARTESIAN_POINT('',(-1.51374069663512,0.857353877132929,-0.0826538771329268));
#644=CARTESIAN_POINT('',(-1.33135779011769,0.852155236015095,-0.077455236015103));
#645=CARTESIAN_POINT('',(-1.1854515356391,0.847995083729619,-0.0732950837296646));
#646=CARTESIAN_POINT('',(-0.747733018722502,0.83551028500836,-0.060810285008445));
#647=CARTESIAN_POINT('',(-0.455921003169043,0.82718129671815,-0.0524812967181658));
#648=CARTESIAN_POINT('',(-0.0182048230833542,0.814655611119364,-0.0399556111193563));
#649=CARTESIAN_POINT('',(0.127700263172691,0.810475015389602,-0.0357750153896));
#650=CARTESIAN_POINT('',(0.419509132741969,0.802091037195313,-0.0273910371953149));
#651=CARTESIAN_POINT('',(0.565412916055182,0.797887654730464,-0.0231876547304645));
#652=CARTESIAN_POINT('',(0.763145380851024,0.792142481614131,-0.017442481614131));
#653=CARTESIAN_POINT('',(0.814975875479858,0.790632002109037,-0.0159320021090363));
#654=CARTESIAN_POINT('',(0.918635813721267,0.787594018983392,-0.0128940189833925));
#655=CARTESIAN_POINT('',(0.970465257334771,0.786066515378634,-0.0113665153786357));
#656=CARTESIAN_POINT('',(1.07412285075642,0.782983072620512,-0.00828307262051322));
#657=CARTESIAN_POINT('',(1.12595100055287,0.781427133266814,-0.00672713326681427));
#658=CARTESIAN_POINT('',(1.2036894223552,0.779030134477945,-0.00433013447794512));
#659=CARTESIAN_POINT('',(1.22960164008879,0.778220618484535,-0.0035206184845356));
#660=CARTESIAN_POINT('',(1.26846768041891,0.776968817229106,-0.00226881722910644));
#661=CARTESIAN_POINT('',(1.2814226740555,0.776545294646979,-0.00184529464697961));
#662=CARTESIAN_POINT('',(1.30733001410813,0.775658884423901,-0.0009588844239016));
#663=CARTESIAN_POINT('',(1.32028236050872,0.775195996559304,-0.000495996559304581));
#664=CARTESIAN_POINT('',(1.3332323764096,0.7747,0.));
#665=B_SPLINE_CURVE_WITH_KNOTS('',3,(#641,#642,#643,#644,#645,#646,#647,#648,#649,#650,#651,
#652,#653,#654,#655,#656,#657,#658,#659,#660,#661,#662,#663,#664),.UNSPECIFIED.,.F.,.F.,(4,2,2,
2,2,2,2,2,2,2,2,4),(0.,0.109518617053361,0.547593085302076,1.42374202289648,1.86181649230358,
2.29989096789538,2.45551444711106,2.61113778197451,2.76676221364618,2.8445746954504,
2.88348110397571,2.92238773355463),.UNSPECIFIED.);
#666=EDGE_CURVE('E79',#639,#508,#665,.T.);
#667=ORIENTED_EDGE('',*,*,#622,.T.);
#668=ORIENTED_EDGE('',*,*,#640,.T.);
#669=ORIENTED_EDGE('',*,*,#666,.T.);
#670=EDGE_LOOP('',(#667,#668,#669));
#671=FACE_BOUND('',#670,.T.);
#672=ADVANCED_FACE('F356',(#671),#491,.T.);
#673=CARTESIAN_POINT('',(1.7526,0.7747,0.));
#674=DIRECTION('',(0.,0.707106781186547,-0.707106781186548));
#675=DIRECTION('',(0.,0.707106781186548,0.707106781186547));
#676=AXIS2_PLACEMENT_3D('',#673,#674,#675);
#677=PLANE('',#676);
#678=DIRECTION('',(-1.,0.,0.));
#679=VECTOR('',#678,1.);
#680=CARTESIAN_POINT('',(1.7526,0.7747,0.));
#681=LINE('',#680,#679);
#682=CARTESIAN_POINT('',(-1.5875,0.7747,0.));
#683=VERTEX_POINT('',#682);
#684=EDGE_CURVE('E220',#508,#683,#681,.T.);
#685=ORIENTED_EDGE('',*,*,#684,.T.);
#686=CARTESIAN_POINT('',(0.147515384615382,0.38735,-0.38735));
#687=DIRECTION('',(0.,0.707106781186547,-0.707106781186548));
#688=DIRECTION('',(0.,0.707106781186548,0.707106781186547));
#689=AXIS2_PLACEMENT_3D('',#686,#687,#688);
#690=CIRCLE('',#689,1.81943904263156);
#691=EDGE_CURVE('E331',#683,#510,#690,.T.);
#692=ORIENTED_EDGE('',*,*,#691,.T.);
#693=ORIENTED_EDGE('',*,*,#511,.F.);
#694=EDGE_LOOP('',(#685,#692,#693));
#695=FACE_BOUND('',#694,.T.);
#696=ADVANCED_FACE('F359',(#695),#677,.T.);
#697=CARTESIAN_POINT('',(1.7526,0.7747,0.));
#698=DIRECTION('',(0.,0.707106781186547,0.707106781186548));
#699=DIRECTION('',(0.,-0.707106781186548,0.707106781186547));
#700=AXIS2_PLACEMENT_3D('',#697,#698,#699);
#701=PLANE('',#700);
#702=ORIENTED_EDGE('',*,*,#666,.F.);
#703=CARTESIAN_POINT('',(0.147515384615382,0.387349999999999,0.38735));
#704=DIRECTION('',(0.,0.707106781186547,0.707106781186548));
#705=DIRECTION('',(0.,-0.707106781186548,0.707106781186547));
#706=AXIS2_PLACEMENT_3D('',#703,#704,#705);
#707=CIRCLE('',#706,1.81943904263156);
#708=EDGE_CURVE('E332',#639,#683,#707,.T.);
#709=ORIENTED_EDGE('',*,*,#708,.T.);
#710=ORIENTED_EDGE('',*,*,#684,.F.);
#711=EDGE_LOOP('',(#702,#709,#710));
#712=FACE_BOUND('',#711,.T.);
#713=ADVANCED_FACE('F388',(#712),#701,.T.);
#714=CARTESIAN_POINT('',(1.7526,-0.387349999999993,-0.670909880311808));
#715=DIRECTION('',(0.,-0.965925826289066,-0.258819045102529));
#716=DIRECTION('',(0.,0.258819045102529,-0.965925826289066));
#717=AXIS2_PLACEMENT_3D('',#714,#715,#716);
#718=PLANE('',#717);
#719=DIRECTION('',(-1.,0.,0.));
#720=VECTOR('',#719,1.);
#721=CARTESIAN_POINT('',(1.7526,-0.387349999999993,-0.670909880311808));
#722=LINE('',#721,#720);
#723=CARTESIAN_POINT('',(-1.5875,-0.387349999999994,-0.670909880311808));
#724=VERTEX_POINT('',#723);
#725=EDGE_CURVE('E215',#290,#724,#722,.T.);
#726=ORIENTED_EDGE('',*,*,#725,.T.);
#727=CARTESIAN_POINT('',(0.147515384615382,-0.529129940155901,-0.141779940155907));
#728=DIRECTION('',(0.,-0.965925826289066,-0.258819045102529));
#729=DIRECTION('',(0.,0.258819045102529,-0.965925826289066));
#730=AXIS2_PLACEMENT_3D('',#727,#728,#729);
#731=CIRCLE('',#730,1.81943904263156);
#732=EDGE_CURVE('E323',#724,#292,#731,.T.);
#733=ORIENTED_EDGE('',*,*,#732,.T.);
#734=ORIENTED_EDGE('',*,*,#293,.F.);
#735=EDGE_LOOP('',(#726,#733,#734));
#736=FACE_BOUND('',#735,.T.);
#737=ADVANCED_FACE('F281',(#736),#718,.T.);
#738=CARTESIAN_POINT('',(1.7526,-0.387349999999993,-0.670909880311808));
#739=DIRECTION('',(0.,0.258819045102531,-0.965925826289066));
#740=DIRECTION('',(0.,0.965925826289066,0.258819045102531));
#741=AXIS2_PLACEMENT_3D('',#738,#739,#740);
#742=PLANE('',#741);
#743=ORIENTED_EDGE('',*,*,#448,.F.);
#744=CARTESIAN_POINT('',(0.147515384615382,0.141779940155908,-0.5291299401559));
#745=DIRECTION('',(0.,0.258819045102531,-0.965925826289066));
#746=DIRECTION('',(0.,0.965925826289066,0.258819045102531));
#747=AXIS2_PLACEMENT_3D('',#744,#745,#746);
#748=CIRCLE('',#747,1.81943904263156);
#749=EDGE_CURVE('E321',#421,#724,#748,.T.);
#750=ORIENTED_EDGE('',*,*,#749,.T.);
#751=ORIENTED_EDGE('',*,*,#725,.F.);
#752=EDGE_LOOP('',(#743,#750,#751));
#753=FACE_BOUND('',#752,.T.);
#754=ADVANCED_FACE('F204',(#753),#742,.T.);
#755=CARTESIAN_POINT('',(1.7526,-0.387350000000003,0.670909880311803));
#756=DIRECTION('',(0.,0.258819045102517,0.965925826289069));
#757=DIRECTION('',(0.,-0.965925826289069,0.258819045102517));
#758=AXIS2_PLACEMENT_3D('',#755,#756,#757);
#759=PLANE('',#758);
#760=DIRECTION('',(-1.,0.,0.));
#761=VECTOR('',#760,1.);
#762=CARTESIAN_POINT('',(1.7526,-0.387350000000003,0.670909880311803));
#763=LINE('',#762,#761);
#764=CARTESIAN_POINT('',(-1.5875,-0.387350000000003,0.670909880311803));
#765=VERTEX_POINT('',#764);
#766=EDGE_CURVE('E165',#72,#765,#763,.T.);
#767=ORIENTED_EDGE('',*,*,#766,.T.);
#768=CARTESIAN_POINT('',(0.147515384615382,0.1417799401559,0.529129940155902));
#769=DIRECTION('',(0.,0.258819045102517,0.965925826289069));
#770=DIRECTION('',(0.,-0.965925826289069,0.258819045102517));
#771=AXIS2_PLACEMENT_3D('',#768,#769,#770);
#772=CIRCLE('',#771,1.81943904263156);
#773=EDGE_CURVE('E152',#765,#74,#772,.T.);
#774=ORIENTED_EDGE('',*,*,#773,.T.);
#775=ORIENTED_EDGE('',*,*,#75,.F.);
#776=EDGE_LOOP('',(#767,#774,#775));
#777=FACE_BOUND('',#776,.T.);
#778=ADVANCED_FACE('F200',(#777),#759,.T.);
#779=CARTESIAN_POINT('',(1.7526,-0.387350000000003,0.670909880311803));
#780=DIRECTION('',(0.,-0.96592582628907,0.258819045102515));
#781=DIRECTION('',(0.,-0.258819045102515,-0.96592582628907));
#782=AXIS2_PLACEMENT_3D('',#779,#780,#781);
#783=PLANE('',#782);
#784=ORIENTED_EDGE('',*,*,#230,.F.);
#785=CARTESIAN_POINT('',(0.147515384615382,-0.529129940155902,0.141779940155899));
#786=DIRECTION('',(0.,-0.96592582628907,0.258819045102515));
#787=DIRECTION('',(0.,-0.258819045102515,-0.96592582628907));
#788=AXIS2_PLACEMENT_3D('',#785,#786,#787);
#789=CIRCLE('',#788,1.81943904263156);
#790=EDGE_CURVE('E12',#203,#765,#789,.T.);
#791=ORIENTED_EDGE('',*,*,#790,.T.);
#792=ORIENTED_EDGE('',*,*,#766,.F.);
#793=EDGE_LOOP('',(#784,#791,#792));
#794=FACE_BOUND('',#793,.T.);
#795=ADVANCED_FACE('F161',(#794),#783,.T.);
#796=CARTESIAN_POINT('',(0.147515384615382,0.,0.));
#797=DIRECTION('',(1.,0.,0.));
#798=DIRECTION('',(0.,1.,0.));
#799=AXIS2_PLACEMENT_3D('',#796,#797,#798);
#800=SPHERICAL_SURFACE('',#799,1.90011538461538);
#801=CARTESIAN_POINT('',(-1.5875,0.,0.));
#802=DIRECTION('',(1.,0.,0.));
#803=DIRECTION('',(0.,1.,0.));
#804=AXIS2_PLACEMENT_3D('',#801,#802,#803);
#805=CIRCLE('',#804,0.7747);
#806=EDGE_CURVE('E243',#528,#185,#805,.T.);
#807=ORIENTED_EDGE('',*,*,#806,.F.);
#808=ORIENTED_EDGE('',*,*,#529,.F.);
#809=ORIENTED_EDGE('',*,*,#691,.F.);
#810=ORIENTED_EDGE('',*,*,#708,.F.);
#811=ORIENTED_EDGE('',*,*,#640,.F.);
#812=EDGE_CURVE('E217',#310,#621,#805,.T.);
#813=ORIENTED_EDGE('',*,*,#812,.F.);
#814=ORIENTED_EDGE('',*,*,#311,.F.);
#815=ORIENTED_EDGE('',*,*,#732,.F.);
#816=ORIENTED_EDGE('',*,*,#749,.F.);
#817=ORIENTED_EDGE('',*,*,#422,.F.);
#818=EDGE_CURVE('E228',#92,#403,#805,.T.);
#819=ORIENTED_EDGE('',*,*,#818,.F.);
#820=ORIENTED_EDGE('',*,*,#93,.F.);
#821=ORIENTED_EDGE('',*,*,#773,.F.);
#822=ORIENTED_EDGE('',*,*,#790,.F.);
#823=ORIENTED_EDGE('',*,*,#204,.F.);
#824=EDGE_LOOP('',(#807,#808,#809,#810,#811,#813,#814,#815,#816,#817,#819,#820,#821,#822,#823));
#825=FACE_BOUND('',#824,.T.);
#826=ADVANCED_FACE('F80',(#825),#800,.T.);
#827=CARTESIAN_POINT('',(-0.147515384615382,0.,0.));
#828=DIRECTION('',(1.,0.,0.));
#829=DIRECTION('',(0.,-1.,0.));
#830=AXIS2_PLACEMENT_3D('',#827,#828,#829);
#831=SPHERICAL_SURFACE('',#830,1.90011538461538);
#832=CARTESIAN_POINT('',(1.5875,0.,0.));
#833=DIRECTION('',(1.,0.,0.));
#834=DIRECTION('',(0.,1.,0.));
#835=AXIS2_PLACEMENT_3D('',#832,#833,#834);
#836=CIRCLE('',#835,0.7747);
#837=CARTESIAN_POINT('',(1.5875,0.7747,0.));
#838=VERTEX_POINT('',#837);
#839=EDGE_CURVE('E415',#838,#838,#836,.T.);
#840=ORIENTED_EDGE('',*,*,#839,.T.);
#841=EDGE_LOOP('',(#840));
#842=FACE_BOUND('',#841,.T.);
#843=ADVANCED_FACE('F419',(#842),#831,.T.);
#844=CARTESIAN_POINT('',(-1.7526,0.,0.));
#845=DIRECTION('',(1.,0.,0.));
#846=DIRECTION('',(0.,1.,0.));
#847=AXIS2_PLACEMENT_3D('',#844,#845,#846);
#848=CYLINDRICAL_SURFACE('',#847,0.7747);
#849=ORIENTED_EDGE('',*,*,#839,.F.);
#850=EDGE_LOOP('',(#849));
#851=FACE_BOUND('',#850,.T.);
#852=ORIENTED_EDGE('',*,*,#186,.F.);
#853=ORIENTED_EDGE('',*,*,#177,.F.);
#854=ORIENTED_EDGE('',*,*,#818,.T.);
#855=ORIENTED_EDGE('',*,*,#404,.F.);
#856=ORIENTED_EDGE('',*,*,#395,.F.);
#857=ORIENTED_EDGE('',*,*,#812,.T.);
#858=ORIENTED_EDGE('',*,*,#622,.F.);
#859=ORIENTED_EDGE('',*,*,#613,.F.);
#860=ORIENTED_EDGE('',*,*,#806,.T.);
#861=EDGE_LOOP('',(#852,#853,#854,#855,#856,#857,#858,#859,#860));
#862=FACE_BOUND('',#861,.T.);
#863=ADVANCED_FACE('F275',(#851,#862),#848,.T.);
#864=CLOSED_SHELL('',(#183,#236,#401,#454,#619,#672,#696,#713,#737,#754,#778,#795,#826,#843,#863));
#865=MANIFOLD_SOLID_BREP('B2',#864);
#866=ADVANCED_BREP_SHAPE_REPRESENTATION('',(#18,#865),#14);
#867=SHAPE_DEFINITION_REPRESENTATION(#9,#866);
ENDSEC;
END-ISO-10303-21;
